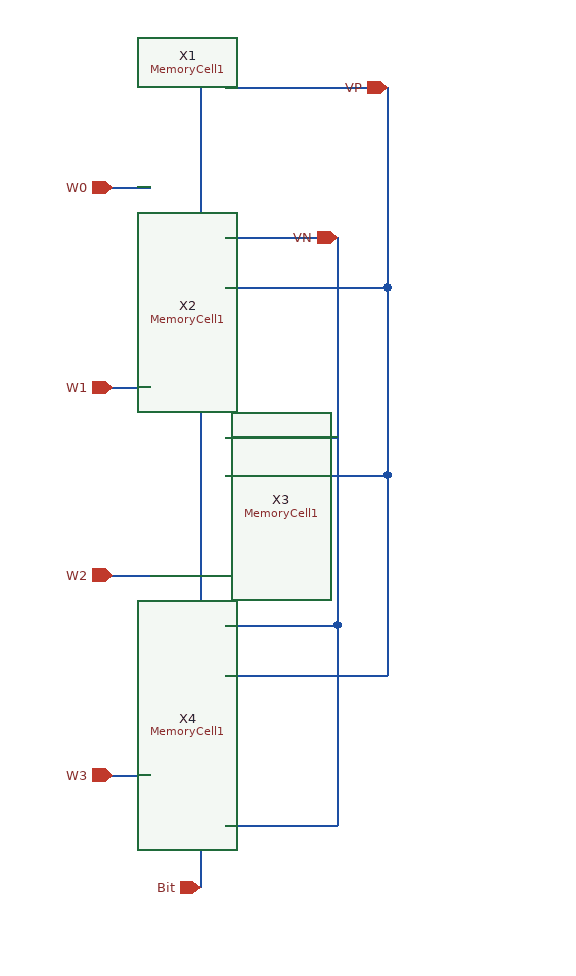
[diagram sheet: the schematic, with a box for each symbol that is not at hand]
v {xschem version=2.9.9 file_version=1.2 }
G {}
K {}
V {}
S {}
E {}
N 170 430 260 430 { lab=VN}
N 170 280 260 280 { lab=VN}
N 170 120 260 120 { lab=VN}
N 260 120 260 430 { lab=VN}
N 260 430 260 590 { lab=VN}
N 170 590 260 590 { lab=VN}
N 170 470 300 470 { lab=VP}
N 300 310 300 470 { lab=VP}
N 170 310 300 310 { lab=VP}
N 170 160 300 160 { lab=VP}
N 300 160 300 310 { lab=VP}
N 170 0 300 -0 { lab=VP}
N 300 -0 300 160 { lab=VP}
N 80 80 110 80 { lab=W0}
N 80 240 110 240 { lab=W1}
N 80 390 110 390 { lab=W2}
N 80 550 110 550 { lab=W3}
N 150 -0 150 160 { lab=Bit}
N 150 160 150 310 { lab=Bit}
N 150 310 150 470 { lab=Bit}
N 150 470 150 640 { lab=Bit}
C {devices/iopin.sym} 300 0 3 0 {name=p1 lab=VP}
C {devices/iopin.sym} 260 120 3 0 {name=p2 lab=VN}
C {devices/iopin.sym} 150 640 2 0 {name=p6 lab=Bit}
C {devices/ipin.sym} 80 80 0 0 {name=p3 lab=W0}
C {devices/ipin.sym} 80 240 0 0 {name=p4 lab=W1}
C {devices/ipin.sym} 80 550 0 0 {name=p5 lab=W3}
C {devices/ipin.sym} 80 390 0 0 {name=p7 lab=W2}
C {/home/madvlsi/Desktop/CMOSDRAM/DRAM_Components/Schematic/MemoryCell1.sym} 130 20 0 0 {name=X1}
C {/home/madvlsi/Desktop/CMOSDRAM/DRAM_Components/Schematic/MemoryCell1.sym} 130 180 0 0 {name=X2}
C {/home/madvlsi/Desktop/CMOSDRAM/DRAM_Components/Schematic/MemoryCell1.sym} 130 330 0 0 {name=X3}
C {/home/madvlsi/Desktop/CMOSDRAM/DRAM_Components/Schematic/MemoryCell1.sym} 130 490 0 0 {name=X4}
